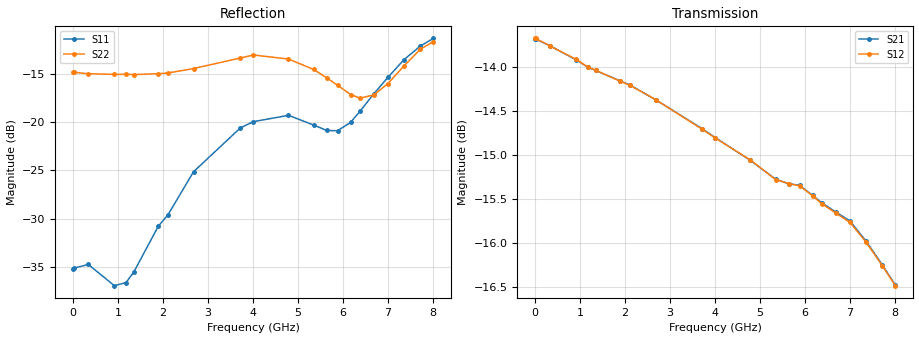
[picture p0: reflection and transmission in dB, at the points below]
! DEVICE ID: PE43712
! File Path: z:\PE43713\PE43713_CHAR_NOM_04292014\AMB\3p300\LS_ATT_12p50dB\PE43713_AMB_3p300V_3p000V_0p000V_LS_ATT_12p50dB_S2P_SN_10_A0139A.s2p
! Serial: 10
! Lot: A0139A
! Temp: 25C
! VDD: 3.300
! VSS: 0.000
! Control_Hi: 3.000
! Control_Lo: 0.000
! Attenuation Step: 12.50dB
! Port 1: RF1
! Port 2: RF2
! ThroughPath:1-2
! IDD: 0.0001469225
! ISS: -8.22e-008
#  Hz  S  RI  R  50
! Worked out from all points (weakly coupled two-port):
!   801 points, 10 MHz to 8.01 GHz, reference 50 ohm
!   highest |S21| = -13.68 dB at 20 MHz (marker M1); lowest = -16.5 dB at 8.01 GHz (marker M2)
!   lowest |S11| = -37.0 dB at 920 MHz (marker M3), VSWR 1.03, Z = 51.3 + j0.54 ohm
!   |S11| at or under -10 dB: start of sweep to end of sweep
!   |S22| runs from -17.6 to -11.7 dB; largest |S21 - S12| = 0.00075
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1e7  0.0174 0.0003  0.207 -0.0011  0.2072 -0.00103  -0.1813 0.00117
2e7  0.0175 0.000562  0.207 -0.00192  0.2072 -0.0019  -0.1811 0.00206
3.4e8  0.0183 0.000328  0.2031 -0.029  0.2031 -0.0285  -0.1767 0.0206
9.2e8  0.0132 0.00526  0.188 -0.0723  0.1881 -0.0724  -0.1684 0.0529
1.18e9  0.0113 0.00948  0.1785 -0.0891  0.1785 -0.0892  -0.1633 0.0676
1.35e9  0.0114 0.0122  0.1719 -0.0996  0.1719 -0.0997  -0.159 0.0758
1.9e9  0.0136 0.0256  0.1464 -0.1302  0.1464 -0.1301  -0.1417 0.1077
2.11e9  0.0147 0.0296  0.1353 -0.1403  0.1353 -0.1402  -0.1357 0.1174
2.68e9  0.023 0.0503  0.1014 -0.1621  0.1013 -0.1622  -0.1103 0.1538
3.72e9  0.0236 0.0902  0.0328 -0.1811  0.0326 -0.181  -0.0852 0.197
4.01e9  0.0222 0.098  0.0137 -0.1814  0.0136 -0.1813  -0.0845 0.2058
4.79e9  0.0198 0.1065  -0.0348 -0.1731  -0.0348 -0.1732  -0.0714 0.1996
5.35e9  0.03 0.0917  -0.0656 -0.1593  -0.0656 -0.1592  -0.0553 0.1788
5.64e9  0.0403 0.081  -0.0802 -0.1513  -0.0801 -0.1514  -0.0359 0.1656
5.88e9  0.051 0.0743  -0.0933 -0.1432  -0.0931 -0.1432  -0.0156 0.1543
6.17e9  0.0699 0.0709  -0.107 -0.1304  -0.1067 -0.1305  0.0142 0.1381
6.38e9  0.0886 0.0713  -0.1151 -0.121  -0.1148 -0.121  0.0385 0.1273
6.68e9  0.1199 0.0713  -0.1262 -0.1064  -0.1259 -0.1064  0.0757 0.1154
7e9  0.1525 0.076  -0.1365 -0.0893  -0.1362 -0.0892  0.1115 0.1121
7.36e9  0.1931 0.0844  -0.1437 -0.0677  -0.1435 -0.0676  0.1557 0.1184
7.72e9  0.2286 0.0943  -0.1465 -0.0474  -0.1463 -0.0475  0.1994 0.1299
8.01e9  0.2498 0.1057  -0.1464 -0.0325  -0.1462 -0.0328  0.2222 0.137
